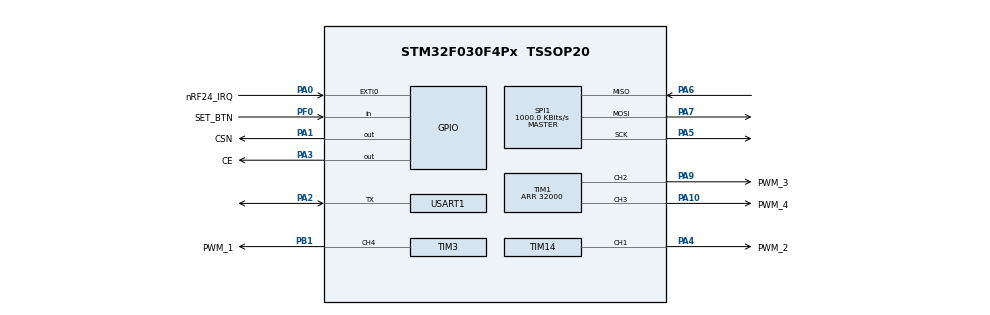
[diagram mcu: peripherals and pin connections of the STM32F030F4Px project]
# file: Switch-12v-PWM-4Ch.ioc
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Mcu.Family=STM32F0
Mcu.Name=STM32F030F4Px
Mcu.Package=TSSOP20
NVIC.EXTI0_1_IRQn=true\:0\:0\:false
NVIC.TIM14_IRQn=true\:0\:0\:false
NVIC.TIM17_IRQn=true\:0\:0\:false
NVIC.TIM3_IRQn=true\:0\:0\:false
PA0.GPIO_Label=nRF24_IRQ
PA0.GPIO_ModeDefaultEXTI=GPIO_MODE_IT_FALLING
PA0.Signal=GPXTI0
PA1.GPIO_Label=CSN
PA1.GPIO_Speed=GPIO_SPEED_HIGH
PA1.PinState=GPIO_PIN_RESET
PA1.Signal=GPIO_Output
PA10.GPIO_Label=PWM_4
PA10.Signal=S_TIM1_CH3
PA2.Mode=Half_duplex(single_wire_mode)
PA2.Signal=USART1_TX
PA3.GPIO_Label=CE
PA3.GPIO_Speed=GPIO_SPEED_HIGH
PA3.Signal=GPIO_Output
PA4.GPIO_Label=PWM_2
PA4.Signal=S_TIM14_CH1
PA5.Mode=Full_Duplex_Master
PA5.Signal=SPI1_SCK
PA6.Mode=Full_Duplex_Master
PA6.Signal=SPI1_MISO
PA7.Mode=Full_Duplex_Master
PA7.Signal=SPI1_MOSI
PA9.GPIO_Label=PWM_3
PA9.Signal=S_TIM1_CH2
PB1.GPIO_Label=PWM_1
PB1.Signal=S_TIM3_CH4
PF0-OSC_IN.GPIO_Label=SET_BTN
PF0-OSC_IN.GPIO_PuPd=GPIO_PULLUP
PF0-OSC_IN.Signal=GPIO_Input
ProjectManager.TargetToolchain=MDK-ARM V5
RCC.AHBCLKDivider=RCC_SYSCLK_DIV2
RCC.AHBFreq_Value=8000000
RCC.APB1Freq_Value=8000000
RCC.APB1TimFreq_Value=8000000
RCC.HCLKFreq_Value=8000000
RCC.PLLMUL=RCC_PLL_MUL4
RCC.SYSCLKFreq_VALUE=16000000
RCC.SYSCLKSource=RCC_SYSCLKSOURCE_PLLCLK
SH.S_TIM14_CH1.0=TIM14_CH1,PWM Generation1 CH1
SH.S_TIM1_CH2.0=TIM1_CH2,PWM Generation2 CH2
SH.S_TIM1_CH3.0=TIM1_CH3,PWM Generation3 CH3
SH.S_TIM3_CH4.0=TIM3_CH4,PWM Generation4 CH4
SPI1.BaudRatePrescaler=SPI_BAUDRATEPRESCALER_8
SPI1.CalculateBaudRate=1000.0 KBits/s
SPI1.DataSize=SPI_DATASIZE_8BIT
SPI1.Mode=SPI_MODE_MASTER
TIM1.Channel-PWM\ Generation2\ CH2=TIM_CHANNEL_2
TIM1.Channel-PWM\ Generation3\ CH3=TIM_CHANNEL_3
TIM1.Period=32000
TIM14.Period=32000
TIM14.Pulse=0
TIM17.Prescaler=1000
TIM3.Channel-PWM\ Generation4\ CH4=TIM_CHANNEL_4
TIM3.Period=32000
USART1.BaudRate=115200
USART1.OverSampling=UART_OVERSAMPLING_16
VP_IWDG_VS_IWDG.Mode=IWDG_Activate
VP_TIM14_VS_ClockSourceINT.Mode=Enable_Timer
VP_TIM17_VS_ClockSourceINT.Mode=Enable_Timer
board=Switch-12v-PWM-4Ch

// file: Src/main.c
/**
  ******************************************************************************
  * File Name          : main.c
  * Description        : Main program body
  ******************************************************************************
  *
  * COPYRIGHT(c) 2016 STMicroelectronics
  *
  * Redistribution and use in source and binary forms, with or without modification,
  * are permitted provided that the following conditions are met:
  *   1. Redistributions of source code must retain the above copyright notice,
  *      this list of conditions and the following disclaimer.
  *   2. Redistributions in binary form must reproduce the above copyright notice,
  *      this list of conditions and the following disclaimer in the documentation
  *      and/or other materials provided with the distribution.
  *   3. Neither the name of STMicroelectronics nor the names of its contributors
  *      may be used to endorse or promote products derived from this software
  *      without specific prior written permission.
  *
  * THIS SOFTWARE IS PROVIDED BY THE COPYRIGHT HOLDERS AND CONTRIBUTORS "AS IS"
  * AND ANY EXPRESS OR IMPLIED WARRANTIES, INCLUDING, BUT NOT LIMITED TO, THE
  * IMPLIED WARRANTIES OF MERCHANTABILITY AND FITNESS FOR A PARTICULAR PURPOSE ARE
  * DISCLAIMED. IN NO EVENT SHALL THE COPYRIGHT HOLDER OR CONTRIBUTORS BE LIABLE
  * FOR ANY DIRECT, INDIRECT, INCIDENTAL, SPECIAL, EXEMPLARY, OR CONSEQUENTIAL
  * DAMAGES (INCLUDING, BUT NOT LIMITED TO, PROCUREMENT OF SUBSTITUTE GOODS OR
  * SERVICES; LOSS OF USE, DATA, OR PROFITS; OR BUSINESS INTERRUPTION) HOWEVER
  * CAUSED AND ON ANY THEORY OF LIABILITY, WHETHER IN CONTRACT, STRICT LIABILITY,
  * OR TORT (INCLUDING NEGLIGENCE OR OTHERWISE) ARISING IN ANY WAY OUT OF THE USE
  * OF THIS SOFTWARE, EVEN IF ADVISED OF THE POSSIBILITY OF SUCH DAMAGE.
  *
  ******************************************************************************
  */
#include "stm32f0xx_hal.h"
#include "iwdg.h"
#include "spi.h"
#include "tim.h"
#include "usart.h"
#include "gpio.h"

/* USER CODE BEGIN Includes */
#include "nRF24L01P.h"
#include "rf_cmd.h"
#include "rf_cmd_exec.h"
#include "config.h"
/* USER CODE END Includes */

/* USER CODE BEGIN PV */
/* Private variables ---------------------------------------------------------*/
uint16_t Tim14PWMPulse = 0;

extern char *CompileTime;
extern char *CompileDate;
uint32_t MCUFreq;

int HandleStatusNeeded = 0x00;
uint32_t SetupInterval = 0x00;
uint8_t Flags = 0x00;
/* USER CODE END PV */

void SystemClock_Config(void);

/* USER CODE BEGIN PFP */
/* Private function prototypes -----------------------------------------------*/

/* USER CODE END PFP */

/* USER CODE BEGIN 0 */
#define PUTCHAR_PROTOTYPE int fputc(int ch, FILE *f)
/* USER CODE END 0 */

int main(void)
{

  /* MCU Configuration----------------------------------------------------------*/

  /* Reset of all peripherals, Initializes the Flash interface and the Systick. */
  HAL_Init();

  /* Configure the system clock */
  SystemClock_Config();

  /* Initialize all configured peripherals */
  MX_GPIO_Init();
  MX_IWDG_Init();
  MX_SPI1_Init();
  MX_TIM14_Init();
  MX_TIM17_Init();
  MX_USART1_UART_Init();
  MX_TIM1_Init();
  MX_TIM3_Init();

  /* USER CODE BEGIN 2 */
  MCUFreq = HAL_RCC_GetSysClockFreq();
  printf("Compiled in: %s at %s!\n\n", CompileDate, CompileTime);

//  printf("SysClockFreq: %08x\n", MCUFreq);
  HAL_TIM_Base_Start(&htim14);
  HAL_TIM_PWM_Start(&htim14, TIM_CHANNEL_1);

  HAL_TIM_Base_Start(&htim1);
  HAL_TIM_PWM_Start(&htim1, TIM_CHANNEL_2 | TIM_CHANNEL_3);

  HAL_TIM_Base_Start(&htim3);
  HAL_TIM_PWM_Start(&htim3, TIM_CHANNEL_4);

  if (configREAD_ADDR_ON_START) {
    readConfig();
  }

  nRF24_SetSPIHandler(&hspi1);
  HAL_Delay(20);

  CE_LOW();
  CSN_HIGH();

  nRF24_RXMode();
  nRF24_HandleStatus();

  HAL_Delay(20);
  CE_HIGH();

  /* USER CODE END 2 */

  /* Infinite loop */
  /* USER CODE BEGIN WHILE */
  while (1)
  {
    if (HandleStatusNeeded) {
      HandleStatusNeeded = 0x00;
      Flags = nRF24_HandleStatus();
    }
//    Flags = nRF24_HandleStatus();
//    HAL_Delay(1500);
/*    if (HAL_GPIO_ReadPin(SET_BTN_GPIO_Port, SET_BTN_Pin) == GPIO_PIN_RESET) {
      if (SetupInterval == 0) {
        SetupInterval = HAL_GetTick();
        nRF24_SetDefaultDeviceAddress();
        nRF24_RXMode();
      }
    }
    if (SetupInterval > 0) {
      if ((HAL_GetTick() - SetupInterval) > configSETUP_TIMEOUT) {
        SetupInterval = 0;
      }
    }
*/
//    HAL_IWDG_Refresh(&hiwdg);
  /* USER CODE END WHILE */

  }

}

/** System Clock Configuration
*/
void SystemClock_Config(void)
{

  RCC_OscInitTypeDef RCC_OscInitStruct;
  RCC_ClkInitTypeDef RCC_ClkInitStruct;
  RCC_PeriphCLKInitTypeDef PeriphClkInit;

  RCC_OscInitStruct.OscillatorType = RCC_OSCILLATORTYPE_HSI|RCC_OSCILLATORTYPE_LSI;
  RCC_OscInitStruct.HSIState = RCC_HSI_ON;
  RCC_OscInitStruct.HSICalibrationValue = 16;
  RCC_OscInitStruct.LSIState = RCC_LSI_ON;
  RCC_OscInitStruct.PLL.PLLState = RCC_PLL_ON;
  RCC_OscInitStruct.PLL.PLLSource = RCC_PLLSOURCE_HSI;
  RCC_OscInitStruct.PLL.PLLMUL = RCC_PLL_MUL12;
  RCC_OscInitStruct.PLL.PREDIV = RCC_PREDIV_DIV1;
  HAL_RCC_OscConfig(&RCC_OscInitStruct);

  RCC_ClkInitStruct.ClockType = RCC_CLOCKTYPE_HCLK|RCC_CLOCKTYPE_SYSCLK
                              |RCC_CLOCKTYPE_PCLK1;
  RCC_ClkInitStruct.SYSCLKSource = RCC_SYSCLKSOURCE_PLLCLK;
  RCC_ClkInitStruct.AHBCLKDivider = RCC_SYSCLK_DIV1;
  RCC_ClkInitStruct.APB1CLKDivider = RCC_HCLK_DIV1;
  HAL_RCC_ClockConfig(&RCC_ClkInitStruct, FLASH_LATENCY_1);

  PeriphClkInit.PeriphClockSelection = RCC_PERIPHCLK_USART1;
  PeriphClkInit.Usart1ClockSelection = RCC_USART1CLKSOURCE_PCLK1;
  HAL_RCCEx_PeriphCLKConfig(&PeriphClkInit);

  HAL_SYSTICK_Config(HAL_RCC_GetHCLKFreq()/1000);

  HAL_SYSTICK_CLKSourceConfig(SYSTICK_CLKSOURCE_HCLK);

  /* SysTick_IRQn interrupt configuration */
  HAL_NVIC_SetPriority(SysTick_IRQn, 0, 0);
}

/* USER CODE BEGIN 4 */

void HAL_GPIO_EXTI_Callback(uint16_t GPIO_Pin) {
  if (GPIO_Pin == GPIO_PIN_13) {
  }
  if (GPIO_Pin == nRF24_IRQ_Pin) {
    printf("HAL_GPIO_EXTI_Callback\n");
    HandleStatusNeeded = 0x01;
  }
}

PUTCHAR_PROTOTYPE
{
  HAL_UART_Transmit(&huart1, (uint8_t *)&ch, 1, 0xFFFF);
  return ch;
}

/* USER CODE END 4 */

/************************ (C) COPYRIGHT STMicroelectronics *****END OF FILE****/
